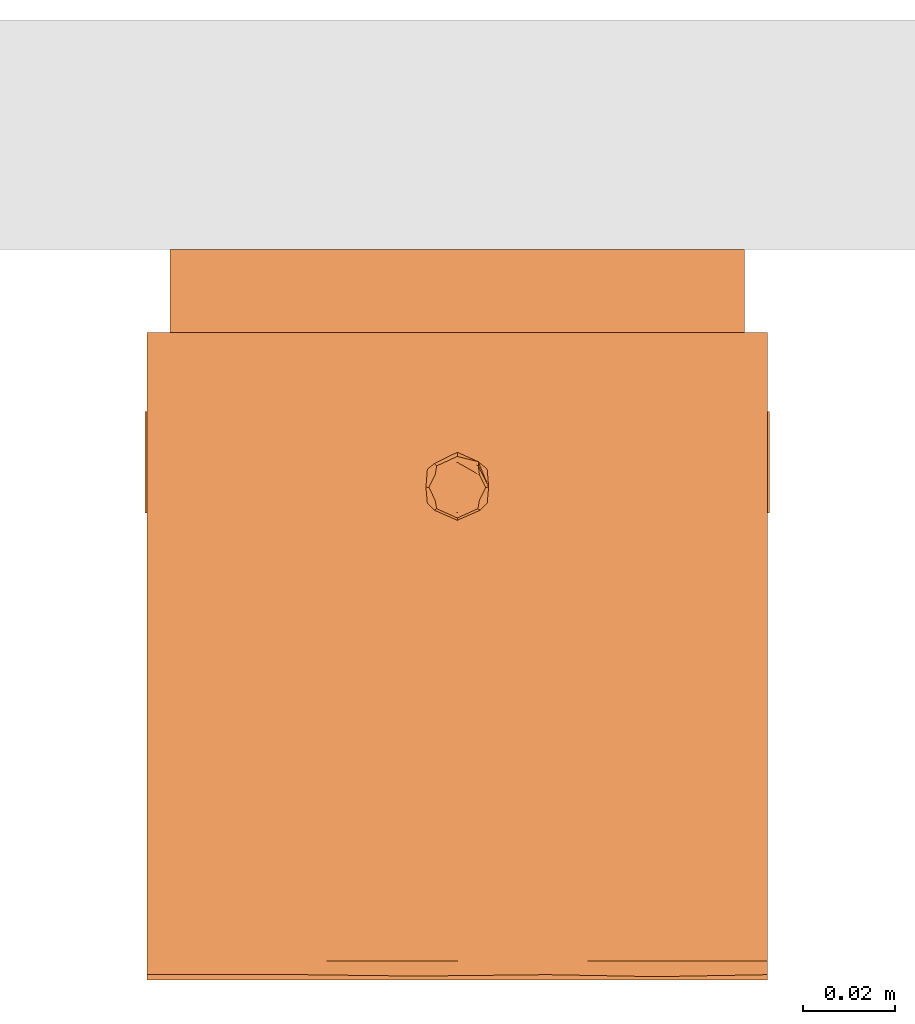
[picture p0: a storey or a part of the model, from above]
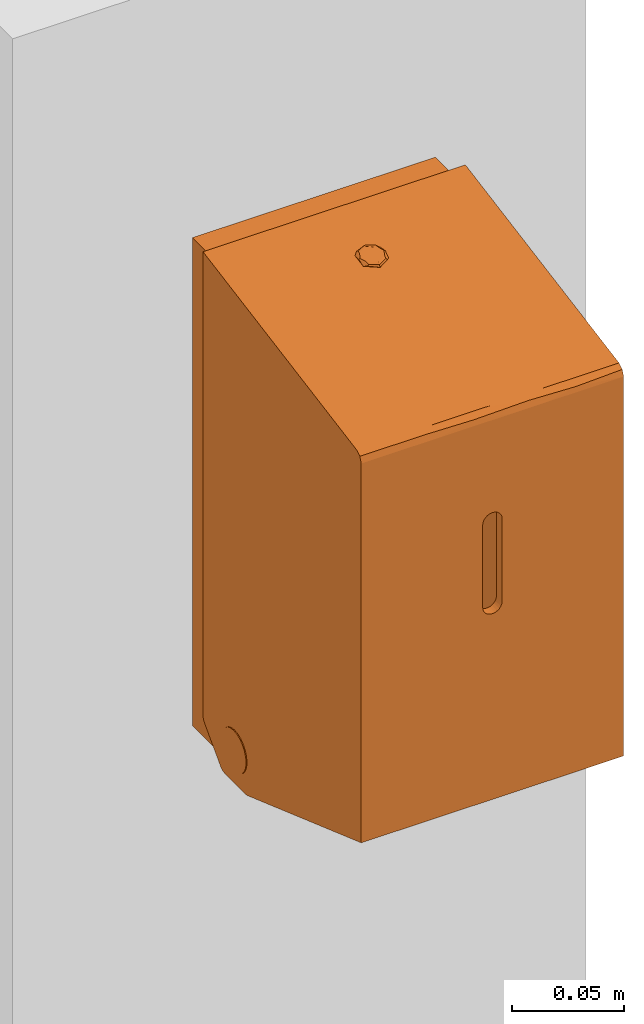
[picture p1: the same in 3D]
Properties of the parts of a building model (IFC2X3)

# File
Description: ViewDefinition [CoordinationView]
Time: 2016-12-01T14:08:41
Written by: The EXPRESS Data Manager Version 5.01.0100.02.64mod : 6 Jun 2012
Made in: 20140709_2115(x64) - Exporter 2014.0.2014.0709 - Default UI
Comment: STEP Physical File produced by: The EXPRESS Data Manager Version 5.01.0100.02.64mod : 6 Jun 2012 * Module: EDMstepFileFactory/EDMstandAlone * Creation date: Thu Dec 01 14:08:41 2016 * Host: BIM-HP * Database: C:\Users\dcole\AppData\Local\Temp\{A4D0C6B6-A6BA-4D60-8A7A-9BE4059BA6A0}\ifc * Database version: 5507 * Database creation date: Thu Dec 01 14:08:39 2016 * Schema: IFC2X3 * Model: DataRepository.ifc * Model creation date: Thu Dec 01 14:08:40 2016 * Header model: DataRepository.ifc_HeaderModel * Header model creation date: Thu Dec 01 14:08:40 2016 * EDMuser: sdai-user * EDMgroup: sdai-group * License ID and type: 5605 : Permanent license. Expiry date: * EDMstepFileFactory options: 020000

# IfcProject
LongName: P:\Fastrack\53721_BELL-CHEM\ADDITIONAL DRAWINGS 2016 BIM\IFC\BC850.ifc

# IfcSite, Default
RefLatitude: 42, 24, 53, 508911; RefLongitude: -71, -15, -29, -58837; RefElevation: 0 mm

# IfcBuilding
Pset_BuildingCommon - NumberOfStoreys: 1

# IfcBuildingStorey, Level 1
LongName: Level 1; Elevation: 0 mm
Constraints - Elevation Base: Project Base Point; Elevation: 0 mm
Identity Data - Name: Level 1; Structural: no; Building Story: yes
Dimensions - Computation Height: 0 mm
Graphics - Line Weight: 1; Symbol at End 1 Default: no; Color: 0; Line Pattern: -3000010; Symbol at End 2 Default: yes

# IfcBuildingElementProxy: BC850 Dolphin Toilet Roll Holder (Special Roll Type), BC850:BC850 Dolphin Toilet Roll Holder (Special Roll Type):32620
In: Level 1
Material: Stainless Steel
Dimensions - Volume: 0.00139786 m3; Projection: 155mm; Depth: 272mm; Width: 135mm
Phasing - Phase Created: New Construction
Constraints - Moves With Nearby Elements: no; Offset: -80.0846 mm; Host: Level : Level 1; Level: Level: Level 1
Pset_ManufacturerTypeInformation - Manufacturer: Dolphin Solutions Ltd.
Pset_BuildingElementProxyCommon - Reference: BC850 Dolphin Toilet Roll Holder (Special Roll Type)
Identity Data - Assembly Description: Other Plumbing Fixtures; Description: Toilet roll holder (special roll type); Tel No.: +44 (0) 1424 202 224; Assembly Code: D2010900; Model: BC850; Type Comments: Same product with Polished finish = BC850B or White metal finish = BC850W; Email: info@dolphinsolutions.co.uk; Fax No.: +44 (0) 1424 205 200; Address: Southpoint, Compass Park, Junction Road, Bodiam, TN32 5BS; URL: www.dolphinsolutions.co.uk; Manufacturer: Dolphin Solutions Ltd.
General - Product Data: Lockable high quality satin stainless steel. Holds 2 special 100m rolls 'pendimatic/ultimatic' type rolls. Inertia brake mechanism prevents paper wastage. Reserve roll drops into place automatically. Also available in white metal finish on request.; Product Page Link: https://www.dolphinsolutions.co.uk/product/toilet-roll-holder-special-roll-type/

# IfcWallStandardCase: Basic Wall:Wall 1, Basic Wall:Wall 1:3092
In: Level 1
Type - PredefinedType: STANDARD; Material: Default Wall 50 mm
Type - Analytical Properties - Absorptance: 0.1; Roughness: 1
Type - Construction - Width: 50 mm; Function: Exterior; Wrapping at Inserts: Do not wrap
Type - Graphics - Coarse Scale Fill Color: 8454143
Dimensions - Volume: 0.00940275 m3; Area: 0.188055 m2; Length: 295 mm
Phasing - Phase Created: New Construction
Constraints - Base Extension Distance: 0 mm; Top Extension Distance: 0 mm; Related to Mass: no; Base Offset: -311.638 mm; Location Line: Finish Face: Interior; Unconnected Height: 637.475 mm; Base Constraint: Level: Level 1; Room Bounding: yes; Base is Attached: no; Top Offset: 0 mm; Top is Attached: no
Structural - Enable Analytical Model: no; Structural: no; Structural Usage: Non-bearing
Pset_WallCommon - Reference: Wall 1; LoadBearing: no; ExtendToStructure: no; IsExternal: yes
